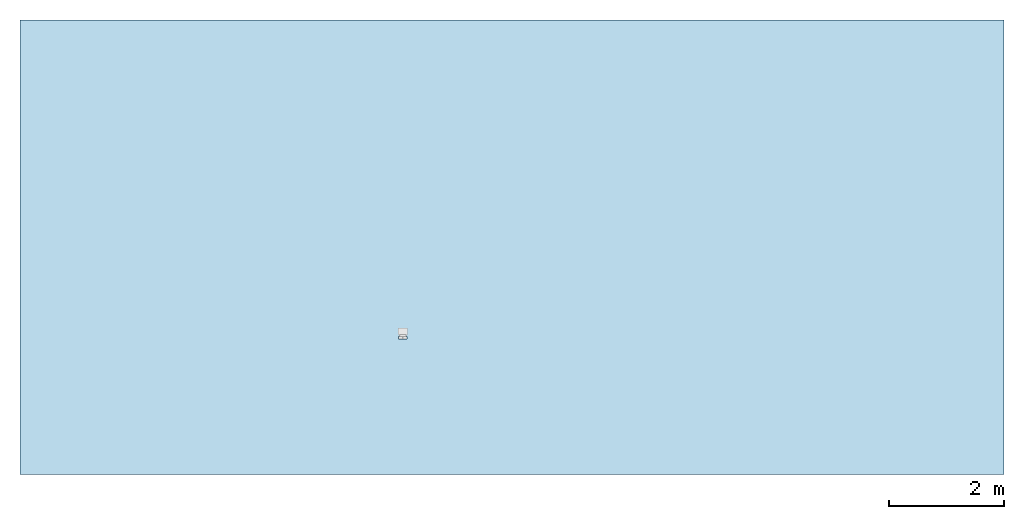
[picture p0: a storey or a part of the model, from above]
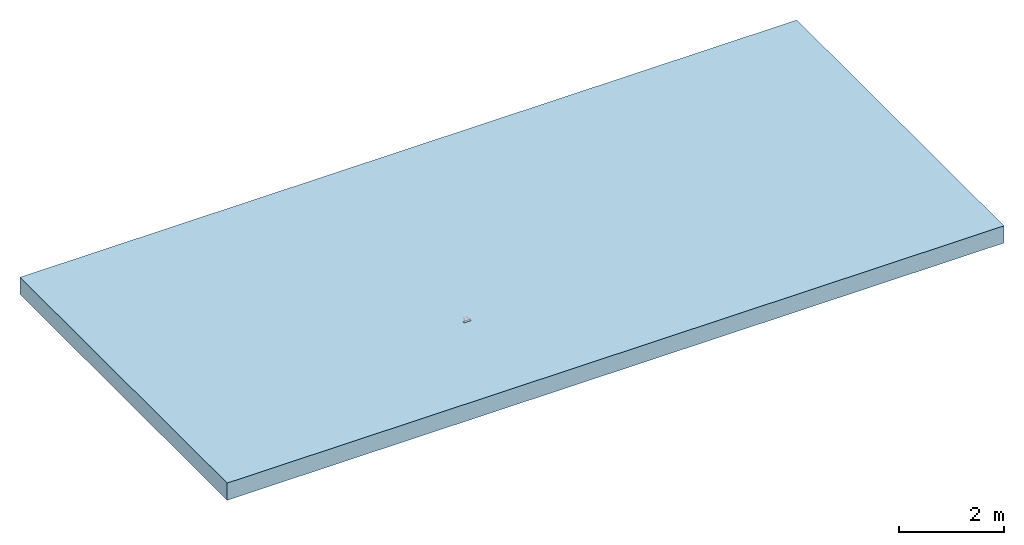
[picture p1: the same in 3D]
Properties of the parts of a building model (IFC2X3)

# File
Description: ViewDefinition [CoordinationView]
File name: 4963 - RH Inlet Outlet End cap.ifc
Time: 2013-08-30T17:55:02
Written by: Autodesk Revit 2013
Made in: 20120221_2030(x64)

# IfcProject, Project Number
LongName: Project Name; Phase: Project Status

# IfcSite, Default
RefLatitude: 42, 21, 30, 344238; RefLongitude: -71, -3, -35, -194702; RefElevation: 0 mm

# IfcBuilding
Pset_BuildingCommon - NumberOfStoreys: 1
Other - Project Issue Date: Issue Date; Project Status: Project Status; Client Name: Owner; Project Address: ## Street City, State Zip; Project Name: Project Name; Project Number: Project Number

# IfcBuildingStorey, Level 1
LongName: Level 1; Elevation: 0 mm
Graphics - Color: 0; Symbol: M_Level Head - Circle: M_Level Head - Circle; Line Weight: 1; Symbol at End 1 Default: no; Line Pattern: Center; Symbol at End 2 Default: yes
Constraints - Elevation Base: 0; Elevation: 0 mm
Dimensions - Computation Height: 0 mm
Identity Data - Structural: no; Name: Level 1; Building Story: yes

# IfcBuildingElementProxy: 4963 - RH Inlet/Outlet End cap, Civil-Drainage-Channel-ACO-KerbDrain-SP480:4963 - RH Inlet/Outlet End cap:4963 - RH Inlet/Outlet End cap:758980
In: Level 1
Material: ACO Polymer Concrete, Acetal Resin, Black
Phasing - Phase Created: New Construction
Constraints - Moves With Nearby Elements: no; Level: Level: Level 1
Dimensions - Volume: 2869516 mm3; Floor Opening Width: 150 mm; Endcap void width: 159.957 mm; Void_Ext_Start: -5.3 mm; Void_Length: -50 mm; Void_Ext_End: 155.2 mm; Endcap void depth: 359 mm
Pset_BuildingElementProxyCommon - Reference: 4963 - RH Inlet/Outlet End cap
Identity Data - Product Code: 4963; URL: www.aco.co.uk; Type Comments: ACO KerbDrain SP480 splayed RH outlet end cap; Product Page URL: http://www.aco.co.uk/product_detail.php?id=3; OmniClass Number: 23.70.50.24; Price: POA - contact ACO; Telephone: +44 (0)1462 816666; Address: ACO Business Park, Hitchin Road, Shefford, Bedfordshire, United Kingdom SG17 5TE; e-mail Technical: technical@aco.co.uk; Fax: +44 (0)1462 815895; Manufacturer: ACO Technologies plc - ACO Water Management Division; Maintenance guidelines: http://www.aco.co.uk/download.php?id=120; Model: ACO KerbDrain SP480; Cost: 0; Assembly Description: Rain Water Drainage; OmniClass Title: Rainwater Removal; Model Description: Combined kerb and drainage system; Assembly Code: D2040; e-mail Sales: customersupport@aco.co.uk; Installation guidelines: http://www.aco.co.uk/download.php?id=120; Product brochure: http://www.aco.co.uk/download.php?id=120
Materials and Finishes - Channel Material: N/A; Channel Colour: N/A; End Cap Colour: Grey; End Cap Material: Vienite® Synthetic Resin Concrete; Connection Pipe Material: Medium Density Polyethylene; Connection Pipe Material Colour: Black
General - SerialNumber: 0.000000; TagNumber: 0.000000
Construction - Inlet/Outlet-RH: yes; EndCap: no; SP480-500: no; Inlet/Outlet-LH: no
Other - CreatedBy: www.aco.co.uk; Revision: 1
Data - Invert Depth: N/A; Product Weight: 5.8 Kg; Installation - Concrete Grade: N/A; Concrete Surround Volume - Load Class A 15 - D 400 - Concrete Pavement: N/A; Channel C.S.A: N/A; Concrete Surround Volume - Load Class A 15 - D 400 - Grass or Asphalt Pavement: N/A; Load Class: N/A; Connection Pipe O.D: Ø160mm; ACO Hydraulic Design Software: N/A; Drainage Slot Intake area: N/A; Hydraulic Performance: N/A; Product Dimensions: 197mm x 150mm x 480mm (LxWxH); Drainage Slot Width: N/A; Product Standard: N/A
Green Building Properties - End Cap Recyclable: Fully recyclable; End Cap Recycled Material Content.: 20% minimum; Channel Recycled Material Content: N/A; Channel Recyclable: N/A

# IfcOpeningElement: Opening
In: Level 1
Structural - Structural: no; Enable Analytical Model: no
Constraints - Room Bounding: yes; Level: Level: Level 1; Height Offset From Level: 0 mm; Related to Mass: no
Dimensions - Thickness: 400 mm; Perimeter: 50000 mm; Area: 135090000 mm2; Volume: 54029286181 mm3
Phasing - Phase Created: New Construction
Analytical Properties - Roughness: 1; Absorptance: 0.1
Graphics - Coarse Scale Fill Color: 0
Construction - Function: 0; Default Thickness: 400 mm
Materials and Finishes - Structural Material: Plant

# IfcSlab: Floor:Generic Floor - 400mm, Floor:Generic Floor - 400mm:193825
In: Level 1
PredefinedType: FLOOR; Material: Plant 400 mm
Structural - Structural: no; Enable Analytical Model: no
Constraints - Room Bounding: yes; Level: Level: Level 1; Height Offset From Level: 0 mm; Related to Mass: no
Dimensions - Thickness: 400 mm; Perimeter: 50000 mm; Area: 135090000 mm2; Volume: 54029286181 mm3
Phasing - Phase Created: New Construction
Pset_SlabCommon - Reference: Generic Floor - 400mm; IsExternal: no; LoadBearing: yes
Analytical Properties - Roughness: 1; Absorptance: 0.1
Graphics - Coarse Scale Fill Color: 0
Construction - Function: 0; Default Thickness: 400 mm
Materials and Finishes - Structural Material: Plant
